VERSION 5.7 ;
BUSBITCHARS "[]" ;
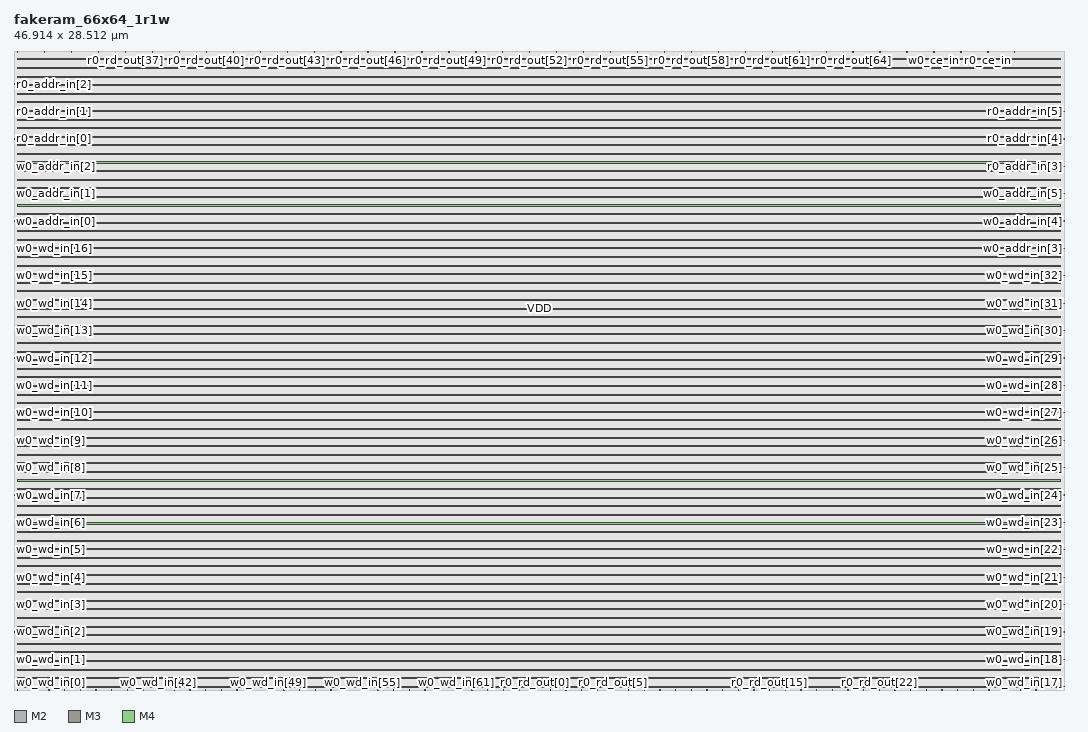
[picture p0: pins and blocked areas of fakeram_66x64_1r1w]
MACRO fakeram_66x64_1r1w
  FOREIGN fakeram_66x64_1r1w 0 0 ;
  SYMMETRY X Y R90 ;
  SIZE 46.914 BY 28.512 ;
  CLASS BLOCK ;
  PIN w0_wd_in[0]
    DIRECTION INPUT ;
    USE SIGNAL ;
    SHAPE ABUTMENT ;
    PORT
      LAYER M2 ;
      RECT 0.000 0.138 0.036 0.150 ;
    END
  END w0_wd_in[0]
  PIN w0_wd_in[1]
    DIRECTION INPUT ;
    USE SIGNAL ;
    SHAPE ABUTMENT ;
    PORT
      LAYER M2 ;
      RECT 0.000 1.362 0.036 1.374 ;
    END
  END w0_wd_in[1]
  PIN w0_wd_in[2]
    DIRECTION INPUT ;
    USE SIGNAL ;
    SHAPE ABUTMENT ;
    PORT
      LAYER M2 ;
      RECT 0.000 2.586 0.036 2.598 ;
    END
  END w0_wd_in[2]
  PIN w0_wd_in[3]
    DIRECTION INPUT ;
    USE SIGNAL ;
    SHAPE ABUTMENT ;
    PORT
      LAYER M2 ;
      RECT 0.000 3.810 0.036 3.822 ;
    END
  END w0_wd_in[3]
  PIN w0_wd_in[4]
    DIRECTION INPUT ;
    USE SIGNAL ;
    SHAPE ABUTMENT ;
    PORT
      LAYER M2 ;
      RECT 0.000 5.034 0.036 5.046 ;
    END
  END w0_wd_in[4]
  PIN w0_wd_in[5]
    DIRECTION INPUT ;
    USE SIGNAL ;
    SHAPE ABUTMENT ;
    PORT
      LAYER M2 ;
      RECT 0.000 6.258 0.036 6.270 ;
    END
  END w0_wd_in[5]
  PIN w0_wd_in[6]
    DIRECTION INPUT ;
    USE SIGNAL ;
    SHAPE ABUTMENT ;
    PORT
      LAYER M2 ;
      RECT 0.000 7.482 0.036 7.494 ;
    END
  END w0_wd_in[6]
  PIN w0_wd_in[7]
    DIRECTION INPUT ;
    USE SIGNAL ;
    SHAPE ABUTMENT ;
    PORT
      LAYER M2 ;
      RECT 0.000 8.706 0.036 8.718 ;
    END
  END w0_wd_in[7]
  PIN w0_wd_in[8]
    DIRECTION INPUT ;
    USE SIGNAL ;
    SHAPE ABUTMENT ;
    PORT
      LAYER M2 ;
      RECT 0.000 9.930 0.036 9.942 ;
    END
  END w0_wd_in[8]
  PIN w0_wd_in[9]
    DIRECTION INPUT ;
    USE SIGNAL ;
    SHAPE ABUTMENT ;
    PORT
      LAYER M2 ;
      RECT 0.000 11.154 0.036 11.166 ;
    END
  END w0_wd_in[9]
  PIN w0_wd_in[10]
    DIRECTION INPUT ;
    USE SIGNAL ;
    SHAPE ABUTMENT ;
    PORT
      LAYER M2 ;
      RECT 0.000 12.378 0.036 12.390 ;
    END
  END w0_wd_in[10]
  PIN w0_wd_in[11]
    DIRECTION INPUT ;
    USE SIGNAL ;
    SHAPE ABUTMENT ;
    PORT
      LAYER M2 ;
      RECT 0.000 13.602 0.036 13.614 ;
    END
  END w0_wd_in[11]
  PIN w0_wd_in[12]
    DIRECTION INPUT ;
    USE SIGNAL ;
    SHAPE ABUTMENT ;
    PORT
      LAYER M2 ;
      RECT 0.000 14.826 0.036 14.838 ;
    END
  END w0_wd_in[12]
  PIN w0_wd_in[13]
    DIRECTION INPUT ;
    USE SIGNAL ;
    SHAPE ABUTMENT ;
    PORT
      LAYER M2 ;
      RECT 0.000 16.050 0.036 16.062 ;
    END
  END w0_wd_in[13]
  PIN w0_wd_in[14]
    DIRECTION INPUT ;
    USE SIGNAL ;
    SHAPE ABUTMENT ;
    PORT
      LAYER M2 ;
      RECT 0.000 17.274 0.036 17.286 ;
    END
  END w0_wd_in[14]
  PIN w0_wd_in[15]
    DIRECTION INPUT ;
    USE SIGNAL ;
    SHAPE ABUTMENT ;
    PORT
      LAYER M2 ;
      RECT 0.000 18.498 0.036 18.510 ;
    END
  END w0_wd_in[15]
  PIN w0_wd_in[16]
    DIRECTION INPUT ;
    USE SIGNAL ;
    SHAPE ABUTMENT ;
    PORT
      LAYER M2 ;
      RECT 0.000 19.722 0.036 19.734 ;
    END
  END w0_wd_in[16]
  PIN w0_wd_in[17]
    DIRECTION INPUT ;
    USE SIGNAL ;
    SHAPE ABUTMENT ;
    PORT
      LAYER M2 ;
      RECT 46.878 0.138 46.914 0.150 ;
    END
  END w0_wd_in[17]
  PIN w0_wd_in[18]
    DIRECTION INPUT ;
    USE SIGNAL ;
    SHAPE ABUTMENT ;
    PORT
      LAYER M2 ;
      RECT 46.878 1.362 46.914 1.374 ;
    END
  END w0_wd_in[18]
  PIN w0_wd_in[19]
    DIRECTION INPUT ;
    USE SIGNAL ;
    SHAPE ABUTMENT ;
    PORT
      LAYER M2 ;
      RECT 46.878 2.586 46.914 2.598 ;
    END
  END w0_wd_in[19]
  PIN w0_wd_in[20]
    DIRECTION INPUT ;
    USE SIGNAL ;
    SHAPE ABUTMENT ;
    PORT
      LAYER M2 ;
      RECT 46.878 3.810 46.914 3.822 ;
    END
  END w0_wd_in[20]
  PIN w0_wd_in[21]
    DIRECTION INPUT ;
    USE SIGNAL ;
    SHAPE ABUTMENT ;
    PORT
      LAYER M2 ;
      RECT 46.878 5.034 46.914 5.046 ;
    END
  END w0_wd_in[21]
  PIN w0_wd_in[22]
    DIRECTION INPUT ;
    USE SIGNAL ;
    SHAPE ABUTMENT ;
    PORT
      LAYER M2 ;
      RECT 46.878 6.258 46.914 6.270 ;
    END
  END w0_wd_in[22]
  PIN w0_wd_in[23]
    DIRECTION INPUT ;
    USE SIGNAL ;
    SHAPE ABUTMENT ;
    PORT
      LAYER M2 ;
      RECT 46.878 7.482 46.914 7.494 ;
    END
  END w0_wd_in[23]
  PIN w0_wd_in[24]
    DIRECTION INPUT ;
    USE SIGNAL ;
    SHAPE ABUTMENT ;
    PORT
      LAYER M2 ;
      RECT 46.878 8.706 46.914 8.718 ;
    END
  END w0_wd_in[24]
  PIN w0_wd_in[25]
    DIRECTION INPUT ;
    USE SIGNAL ;
    SHAPE ABUTMENT ;
    PORT
      LAYER M2 ;
      RECT 46.878 9.930 46.914 9.942 ;
    END
  END w0_wd_in[25]
  PIN w0_wd_in[26]
    DIRECTION INPUT ;
    USE SIGNAL ;
    SHAPE ABUTMENT ;
    PORT
      LAYER M2 ;
      RECT 46.878 11.154 46.914 11.166 ;
    END
  END w0_wd_in[26]
  PIN w0_wd_in[27]
    DIRECTION INPUT ;
    USE SIGNAL ;
    SHAPE ABUTMENT ;
    PORT
      LAYER M2 ;
      RECT 46.878 12.378 46.914 12.390 ;
    END
  END w0_wd_in[27]
  PIN w0_wd_in[28]
    DIRECTION INPUT ;
    USE SIGNAL ;
    SHAPE ABUTMENT ;
    PORT
      LAYER M2 ;
      RECT 46.878 13.602 46.914 13.614 ;
    END
  END w0_wd_in[28]
  PIN w0_wd_in[29]
    DIRECTION INPUT ;
    USE SIGNAL ;
    SHAPE ABUTMENT ;
    PORT
      LAYER M2 ;
      RECT 46.878 14.826 46.914 14.838 ;
    END
  END w0_wd_in[29]
  PIN w0_wd_in[30]
    DIRECTION INPUT ;
    USE SIGNAL ;
    SHAPE ABUTMENT ;
    PORT
      LAYER M2 ;
      RECT 46.878 16.050 46.914 16.062 ;
    END
  END w0_wd_in[30]
  PIN w0_wd_in[31]
    DIRECTION INPUT ;
    USE SIGNAL ;
    SHAPE ABUTMENT ;
    PORT
      LAYER M2 ;
      RECT 46.878 17.274 46.914 17.286 ;
    END
  END w0_wd_in[31]
  PIN w0_wd_in[32]
    DIRECTION INPUT ;
    USE SIGNAL ;
    SHAPE ABUTMENT ;
    PORT
      LAYER M2 ;
      RECT 46.878 18.498 46.914 18.510 ;
    END
  END w0_wd_in[32]
  PIN w0_wd_in[33]
    DIRECTION INPUT ;
    USE SIGNAL ;
    SHAPE ABUTMENT ;
    PORT
      LAYER M3 ;
      RECT 0.161 0.000 0.175 0.042 ;
    END
  END w0_wd_in[33]
  PIN w0_wd_in[34]
    DIRECTION INPUT ;
    USE SIGNAL ;
    SHAPE ABUTMENT ;
    PORT
      LAYER M3 ;
      RECT 0.861 0.000 0.875 0.042 ;
    END
  END w0_wd_in[34]
  PIN w0_wd_in[35]
    DIRECTION INPUT ;
    USE SIGNAL ;
    SHAPE ABUTMENT ;
    PORT
      LAYER M3 ;
      RECT 1.561 0.000 1.575 0.042 ;
    END
  END w0_wd_in[35]
  PIN w0_wd_in[36]
    DIRECTION INPUT ;
    USE SIGNAL ;
    SHAPE ABUTMENT ;
    PORT
      LAYER M3 ;
      RECT 2.261 0.000 2.275 0.042 ;
    END
  END w0_wd_in[36]
  PIN w0_wd_in[37]
    DIRECTION INPUT ;
    USE SIGNAL ;
    SHAPE ABUTMENT ;
    PORT
      LAYER M3 ;
      RECT 2.961 0.000 2.975 0.042 ;
    END
  END w0_wd_in[37]
  PIN w0_wd_in[38]
    DIRECTION INPUT ;
    USE SIGNAL ;
    SHAPE ABUTMENT ;
    PORT
      LAYER M3 ;
      RECT 3.661 0.000 3.675 0.042 ;
    END
  END w0_wd_in[38]
  PIN w0_wd_in[39]
    DIRECTION INPUT ;
    USE SIGNAL ;
    SHAPE ABUTMENT ;
    PORT
      LAYER M3 ;
      RECT 4.361 0.000 4.375 0.042 ;
    END
  END w0_wd_in[39]
  PIN w0_wd_in[40]
    DIRECTION INPUT ;
    USE SIGNAL ;
    SHAPE ABUTMENT ;
    PORT
      LAYER M3 ;
      RECT 5.061 0.000 5.075 0.042 ;
    END
  END w0_wd_in[40]
  PIN w0_wd_in[41]
    DIRECTION INPUT ;
    USE SIGNAL ;
    SHAPE ABUTMENT ;
    PORT
      LAYER M3 ;
      RECT 5.761 0.000 5.775 0.042 ;
    END
  END w0_wd_in[41]
  PIN w0_wd_in[42]
    DIRECTION INPUT ;
    USE SIGNAL ;
    SHAPE ABUTMENT ;
    PORT
      LAYER M3 ;
      RECT 6.461 0.000 6.475 0.042 ;
    END
  END w0_wd_in[42]
  PIN w0_wd_in[43]
    DIRECTION INPUT ;
    USE SIGNAL ;
    SHAPE ABUTMENT ;
    PORT
      LAYER M3 ;
      RECT 7.161 0.000 7.175 0.042 ;
    END
  END w0_wd_in[43]
  PIN w0_wd_in[44]
    DIRECTION INPUT ;
    USE SIGNAL ;
    SHAPE ABUTMENT ;
    PORT
      LAYER M3 ;
      RECT 7.861 0.000 7.875 0.042 ;
    END
  END w0_wd_in[44]
  PIN w0_wd_in[45]
    DIRECTION INPUT ;
    USE SIGNAL ;
    SHAPE ABUTMENT ;
    PORT
      LAYER M3 ;
      RECT 8.561 0.000 8.575 0.042 ;
    END
  END w0_wd_in[45]
  PIN w0_wd_in[46]
    DIRECTION INPUT ;
    USE SIGNAL ;
    SHAPE ABUTMENT ;
    PORT
      LAYER M3 ;
      RECT 9.261 0.000 9.275 0.042 ;
    END
  END w0_wd_in[46]
  PIN w0_wd_in[47]
    DIRECTION INPUT ;
    USE SIGNAL ;
    SHAPE ABUTMENT ;
    PORT
      LAYER M3 ;
      RECT 9.961 0.000 9.975 0.042 ;
    END
  END w0_wd_in[47]
  PIN w0_wd_in[48]
    DIRECTION INPUT ;
    USE SIGNAL ;
    SHAPE ABUTMENT ;
    PORT
      LAYER M3 ;
      RECT 10.661 0.000 10.675 0.042 ;
    END
  END w0_wd_in[48]
  PIN w0_wd_in[49]
    DIRECTION INPUT ;
    USE SIGNAL ;
    SHAPE ABUTMENT ;
    PORT
      LAYER M3 ;
      RECT 11.361 0.000 11.375 0.042 ;
    END
  END w0_wd_in[49]
  PIN w0_wd_in[50]
    DIRECTION INPUT ;
    USE SIGNAL ;
    SHAPE ABUTMENT ;
    PORT
      LAYER M3 ;
      RECT 12.061 0.000 12.075 0.042 ;
    END
  END w0_wd_in[50]
  PIN w0_wd_in[51]
    DIRECTION INPUT ;
    USE SIGNAL ;
    SHAPE ABUTMENT ;
    PORT
      LAYER M3 ;
      RECT 12.761 0.000 12.775 0.042 ;
    END
  END w0_wd_in[51]
  PIN w0_wd_in[52]
    DIRECTION INPUT ;
    USE SIGNAL ;
    SHAPE ABUTMENT ;
    PORT
      LAYER M3 ;
      RECT 13.461 0.000 13.475 0.042 ;
    END
  END w0_wd_in[52]
  PIN w0_wd_in[53]
    DIRECTION INPUT ;
    USE SIGNAL ;
    SHAPE ABUTMENT ;
    PORT
      LAYER M3 ;
      RECT 14.161 0.000 14.175 0.042 ;
    END
  END w0_wd_in[53]
  PIN w0_wd_in[54]
    DIRECTION INPUT ;
    USE SIGNAL ;
    SHAPE ABUTMENT ;
    PORT
      LAYER M3 ;
      RECT 14.861 0.000 14.875 0.042 ;
    END
  END w0_wd_in[54]
  PIN w0_wd_in[55]
    DIRECTION INPUT ;
    USE SIGNAL ;
    SHAPE ABUTMENT ;
    PORT
      LAYER M3 ;
      RECT 15.561 0.000 15.575 0.042 ;
    END
  END w0_wd_in[55]
  PIN w0_wd_in[56]
    DIRECTION INPUT ;
    USE SIGNAL ;
    SHAPE ABUTMENT ;
    PORT
      LAYER M3 ;
      RECT 16.261 0.000 16.275 0.042 ;
    END
  END w0_wd_in[56]
  PIN w0_wd_in[57]
    DIRECTION INPUT ;
    USE SIGNAL ;
    SHAPE ABUTMENT ;
    PORT
      LAYER M3 ;
      RECT 16.961 0.000 16.975 0.042 ;
    END
  END w0_wd_in[57]
  PIN w0_wd_in[58]
    DIRECTION INPUT ;
    USE SIGNAL ;
    SHAPE ABUTMENT ;
    PORT
      LAYER M3 ;
      RECT 17.661 0.000 17.675 0.042 ;
    END
  END w0_wd_in[58]
  PIN w0_wd_in[59]
    DIRECTION INPUT ;
    USE SIGNAL ;
    SHAPE ABUTMENT ;
    PORT
      LAYER M3 ;
      RECT 18.361 0.000 18.375 0.042 ;
    END
  END w0_wd_in[59]
  PIN w0_wd_in[60]
    DIRECTION INPUT ;
    USE SIGNAL ;
    SHAPE ABUTMENT ;
    PORT
      LAYER M3 ;
      RECT 19.061 0.000 19.075 0.042 ;
    END
  END w0_wd_in[60]
  PIN w0_wd_in[61]
    DIRECTION INPUT ;
    USE SIGNAL ;
    SHAPE ABUTMENT ;
    PORT
      LAYER M3 ;
      RECT 19.761 0.000 19.775 0.042 ;
    END
  END w0_wd_in[61]
  PIN w0_wd_in[62]
    DIRECTION INPUT ;
    USE SIGNAL ;
    SHAPE ABUTMENT ;
    PORT
      LAYER M3 ;
      RECT 20.461 0.000 20.475 0.042 ;
    END
  END w0_wd_in[62]
  PIN w0_wd_in[63]
    DIRECTION INPUT ;
    USE SIGNAL ;
    SHAPE ABUTMENT ;
    PORT
      LAYER M3 ;
      RECT 21.161 0.000 21.175 0.042 ;
    END
  END w0_wd_in[63]
  PIN w0_wd_in[64]
    DIRECTION INPUT ;
    USE SIGNAL ;
    SHAPE ABUTMENT ;
    PORT
      LAYER M3 ;
      RECT 21.861 0.000 21.875 0.042 ;
    END
  END w0_wd_in[64]
  PIN w0_wd_in[65]
    DIRECTION INPUT ;
    USE SIGNAL ;
    SHAPE ABUTMENT ;
    PORT
      LAYER M3 ;
      RECT 22.561 0.000 22.575 0.042 ;
    END
  END w0_wd_in[65]
  PIN r0_rd_out[0]
    DIRECTION OUTPUT ;
    USE SIGNAL ;
    SHAPE ABUTMENT ;
    PORT
      LAYER M3 ;
      RECT 23.261 0.000 23.275 0.042 ;
    END
  END r0_rd_out[0]
  PIN r0_rd_out[1]
    DIRECTION OUTPUT ;
    USE SIGNAL ;
    SHAPE ABUTMENT ;
    PORT
      LAYER M3 ;
      RECT 23.961 0.000 23.975 0.042 ;
    END
  END r0_rd_out[1]
  PIN r0_rd_out[2]
    DIRECTION OUTPUT ;
    USE SIGNAL ;
    SHAPE ABUTMENT ;
    PORT
      LAYER M3 ;
      RECT 24.661 0.000 24.675 0.042 ;
    END
  END r0_rd_out[2]
  PIN r0_rd_out[3]
    DIRECTION OUTPUT ;
    USE SIGNAL ;
    SHAPE ABUTMENT ;
    PORT
      LAYER M3 ;
      RECT 25.361 0.000 25.375 0.042 ;
    END
  END r0_rd_out[3]
  PIN r0_rd_out[4]
    DIRECTION OUTPUT ;
    USE SIGNAL ;
    SHAPE ABUTMENT ;
    PORT
      LAYER M3 ;
      RECT 26.061 0.000 26.075 0.042 ;
    END
  END r0_rd_out[4]
  PIN r0_rd_out[5]
    DIRECTION OUTPUT ;
    USE SIGNAL ;
    SHAPE ABUTMENT ;
    PORT
      LAYER M3 ;
      RECT 26.761 0.000 26.775 0.042 ;
    END
  END r0_rd_out[5]
  PIN r0_rd_out[6]
    DIRECTION OUTPUT ;
    USE SIGNAL ;
    SHAPE ABUTMENT ;
    PORT
      LAYER M3 ;
      RECT 27.461 0.000 27.475 0.042 ;
    END
  END r0_rd_out[6]
  PIN r0_rd_out[7]
    DIRECTION OUTPUT ;
    USE SIGNAL ;
    SHAPE ABUTMENT ;
    PORT
      LAYER M3 ;
      RECT 28.161 0.000 28.175 0.042 ;
    END
  END r0_rd_out[7]
  PIN r0_rd_out[8]
    DIRECTION OUTPUT ;
    USE SIGNAL ;
    SHAPE ABUTMENT ;
    PORT
      LAYER M3 ;
      RECT 28.861 0.000 28.875 0.042 ;
    END
  END r0_rd_out[8]
  PIN r0_rd_out[9]
    DIRECTION OUTPUT ;
    USE SIGNAL ;
    SHAPE ABUTMENT ;
    PORT
      LAYER M3 ;
      RECT 29.561 0.000 29.575 0.042 ;
    END
  END r0_rd_out[9]
  PIN r0_rd_out[10]
    DIRECTION OUTPUT ;
    USE SIGNAL ;
    SHAPE ABUTMENT ;
    PORT
      LAYER M3 ;
      RECT 30.261 0.000 30.275 0.042 ;
    END
  END r0_rd_out[10]
  PIN r0_rd_out[11]
    DIRECTION OUTPUT ;
    USE SIGNAL ;
    SHAPE ABUTMENT ;
    PORT
      LAYER M3 ;
      RECT 30.961 0.000 30.975 0.042 ;
    END
  END r0_rd_out[11]
  PIN r0_rd_out[12]
    DIRECTION OUTPUT ;
    USE SIGNAL ;
    SHAPE ABUTMENT ;
    PORT
      LAYER M3 ;
      RECT 31.661 0.000 31.675 0.042 ;
    END
  END r0_rd_out[12]
  PIN r0_rd_out[13]
    DIRECTION OUTPUT ;
    USE SIGNAL ;
    SHAPE ABUTMENT ;
    PORT
      LAYER M3 ;
      RECT 32.361 0.000 32.375 0.042 ;
    END
  END r0_rd_out[13]
  PIN r0_rd_out[14]
    DIRECTION OUTPUT ;
    USE SIGNAL ;
    SHAPE ABUTMENT ;
    PORT
      LAYER M3 ;
      RECT 33.061 0.000 33.075 0.042 ;
    END
  END r0_rd_out[14]
  PIN r0_rd_out[15]
    DIRECTION OUTPUT ;
    USE SIGNAL ;
    SHAPE ABUTMENT ;
    PORT
      LAYER M3 ;
      RECT 33.761 0.000 33.775 0.042 ;
    END
  END r0_rd_out[15]
  PIN r0_rd_out[16]
    DIRECTION OUTPUT ;
    USE SIGNAL ;
    SHAPE ABUTMENT ;
    PORT
      LAYER M3 ;
      RECT 34.461 0.000 34.475 0.042 ;
    END
  END r0_rd_out[16]
  PIN r0_rd_out[17]
    DIRECTION OUTPUT ;
    USE SIGNAL ;
    SHAPE ABUTMENT ;
    PORT
      LAYER M3 ;
      RECT 35.161 0.000 35.175 0.042 ;
    END
  END r0_rd_out[17]
  PIN r0_rd_out[18]
    DIRECTION OUTPUT ;
    USE SIGNAL ;
    SHAPE ABUTMENT ;
    PORT
      LAYER M3 ;
      RECT 35.861 0.000 35.875 0.042 ;
    END
  END r0_rd_out[18]
  PIN r0_rd_out[19]
    DIRECTION OUTPUT ;
    USE SIGNAL ;
    SHAPE ABUTMENT ;
    PORT
      LAYER M3 ;
      RECT 36.561 0.000 36.575 0.042 ;
    END
  END r0_rd_out[19]
  PIN r0_rd_out[20]
    DIRECTION OUTPUT ;
    USE SIGNAL ;
    SHAPE ABUTMENT ;
    PORT
      LAYER M3 ;
      RECT 37.261 0.000 37.275 0.042 ;
    END
  END r0_rd_out[20]
  PIN r0_rd_out[21]
    DIRECTION OUTPUT ;
    USE SIGNAL ;
    SHAPE ABUTMENT ;
    PORT
      LAYER M3 ;
      RECT 37.961 0.000 37.975 0.042 ;
    END
  END r0_rd_out[21]
  PIN r0_rd_out[22]
    DIRECTION OUTPUT ;
    USE SIGNAL ;
    SHAPE ABUTMENT ;
    PORT
      LAYER M3 ;
      RECT 38.661 0.000 38.675 0.042 ;
    END
  END r0_rd_out[22]
  PIN r0_rd_out[23]
    DIRECTION OUTPUT ;
    USE SIGNAL ;
    SHAPE ABUTMENT ;
    PORT
      LAYER M3 ;
      RECT 39.361 0.000 39.375 0.042 ;
    END
  END r0_rd_out[23]
  PIN r0_rd_out[24]
    DIRECTION OUTPUT ;
    USE SIGNAL ;
    SHAPE ABUTMENT ;
    PORT
      LAYER M3 ;
      RECT 40.061 0.000 40.075 0.042 ;
    END
  END r0_rd_out[24]
  PIN r0_rd_out[25]
    DIRECTION OUTPUT ;
    USE SIGNAL ;
    SHAPE ABUTMENT ;
    PORT
      LAYER M3 ;
      RECT 40.761 0.000 40.775 0.042 ;
    END
  END r0_rd_out[25]
  PIN r0_rd_out[26]
    DIRECTION OUTPUT ;
    USE SIGNAL ;
    SHAPE ABUTMENT ;
    PORT
      LAYER M3 ;
      RECT 41.461 0.000 41.475 0.042 ;
    END
  END r0_rd_out[26]
  PIN r0_rd_out[27]
    DIRECTION OUTPUT ;
    USE SIGNAL ;
    SHAPE ABUTMENT ;
    PORT
      LAYER M3 ;
      RECT 42.161 0.000 42.175 0.042 ;
    END
  END r0_rd_out[27]
  PIN r0_rd_out[28]
    DIRECTION OUTPUT ;
    USE SIGNAL ;
    SHAPE ABUTMENT ;
    PORT
      LAYER M3 ;
      RECT 42.861 0.000 42.875 0.042 ;
    END
  END r0_rd_out[28]
  PIN r0_rd_out[29]
    DIRECTION OUTPUT ;
    USE SIGNAL ;
    SHAPE ABUTMENT ;
    PORT
      LAYER M3 ;
      RECT 43.561 0.000 43.575 0.042 ;
    END
  END r0_rd_out[29]
  PIN r0_rd_out[30]
    DIRECTION OUTPUT ;
    USE SIGNAL ;
    SHAPE ABUTMENT ;
    PORT
      LAYER M3 ;
      RECT 44.261 0.000 44.275 0.042 ;
    END
  END r0_rd_out[30]
  PIN r0_rd_out[31]
    DIRECTION OUTPUT ;
    USE SIGNAL ;
    SHAPE ABUTMENT ;
    PORT
      LAYER M3 ;
      RECT 44.961 0.000 44.975 0.042 ;
    END
  END r0_rd_out[31]
  PIN r0_rd_out[32]
    DIRECTION OUTPUT ;
    USE SIGNAL ;
    SHAPE ABUTMENT ;
    PORT
      LAYER M3 ;
      RECT 45.661 0.000 45.675 0.042 ;
    END
  END r0_rd_out[32]
  PIN r0_rd_out[33]
    DIRECTION OUTPUT ;
    USE SIGNAL ;
    SHAPE ABUTMENT ;
    PORT
      LAYER M3 ;
      RECT 0.161 28.470 0.175 28.512 ;
    END
  END r0_rd_out[33]
  PIN r0_rd_out[34]
    DIRECTION OUTPUT ;
    USE SIGNAL ;
    SHAPE ABUTMENT ;
    PORT
      LAYER M3 ;
      RECT 1.365 28.470 1.379 28.512 ;
    END
  END r0_rd_out[34]
  PIN r0_rd_out[35]
    DIRECTION OUTPUT ;
    USE SIGNAL ;
    SHAPE ABUTMENT ;
    PORT
      LAYER M3 ;
      RECT 2.569 28.470 2.583 28.512 ;
    END
  END r0_rd_out[35]
  PIN r0_rd_out[36]
    DIRECTION OUTPUT ;
    USE SIGNAL ;
    SHAPE ABUTMENT ;
    PORT
      LAYER M3 ;
      RECT 3.773 28.470 3.787 28.512 ;
    END
  END r0_rd_out[36]
  PIN r0_rd_out[37]
    DIRECTION OUTPUT ;
    USE SIGNAL ;
    SHAPE ABUTMENT ;
    PORT
      LAYER M3 ;
      RECT 4.977 28.470 4.991 28.512 ;
    END
  END r0_rd_out[37]
  PIN r0_rd_out[38]
    DIRECTION OUTPUT ;
    USE SIGNAL ;
    SHAPE ABUTMENT ;
    PORT
      LAYER M3 ;
      RECT 6.181 28.470 6.195 28.512 ;
    END
  END r0_rd_out[38]
  PIN r0_rd_out[39]
    DIRECTION OUTPUT ;
    USE SIGNAL ;
    SHAPE ABUTMENT ;
    PORT
      LAYER M3 ;
      RECT 7.385 28.470 7.399 28.512 ;
    END
  END r0_rd_out[39]
  PIN r0_rd_out[40]
    DIRECTION OUTPUT ;
    USE SIGNAL ;
    SHAPE ABUTMENT ;
    PORT
      LAYER M3 ;
      RECT 8.589 28.470 8.603 28.512 ;
    END
  END r0_rd_out[40]
  PIN r0_rd_out[41]
    DIRECTION OUTPUT ;
    USE SIGNAL ;
    SHAPE ABUTMENT ;
    PORT
      LAYER M3 ;
      RECT 9.793 28.470 9.807 28.512 ;
    END
  END r0_rd_out[41]
  PIN r0_rd_out[42]
    DIRECTION OUTPUT ;
    USE SIGNAL ;
    SHAPE ABUTMENT ;
    PORT
      LAYER M3 ;
      RECT 10.997 28.470 11.011 28.512 ;
    END
  END r0_rd_out[42]
  PIN r0_rd_out[43]
    DIRECTION OUTPUT ;
    USE SIGNAL ;
    SHAPE ABUTMENT ;
    PORT
      LAYER M3 ;
      RECT 12.201 28.470 12.215 28.512 ;
    END
  END r0_rd_out[43]
  PIN r0_rd_out[44]
    DIRECTION OUTPUT ;
    USE SIGNAL ;
    SHAPE ABUTMENT ;
    PORT
      LAYER M3 ;
      RECT 13.405 28.470 13.419 28.512 ;
    END
  END r0_rd_out[44]
  PIN r0_rd_out[45]
    DIRECTION OUTPUT ;
    USE SIGNAL ;
    SHAPE ABUTMENT ;
    PORT
      LAYER M3 ;
      RECT 14.609 28.470 14.623 28.512 ;
    END
  END r0_rd_out[45]
  PIN r0_rd_out[46]
    DIRECTION OUTPUT ;
    USE SIGNAL ;
    SHAPE ABUTMENT ;
    PORT
      LAYER M3 ;
      RECT 15.813 28.470 15.827 28.512 ;
    END
  END r0_rd_out[46]
  PIN r0_rd_out[47]
    DIRECTION OUTPUT ;
    USE SIGNAL ;
    SHAPE ABUTMENT ;
    PORT
      LAYER M3 ;
      RECT 17.017 28.470 17.031 28.512 ;
    END
  END r0_rd_out[47]
  PIN r0_rd_out[48]
    DIRECTION OUTPUT ;
    USE SIGNAL ;
    SHAPE ABUTMENT ;
    PORT
      LAYER M3 ;
      RECT 18.221 28.470 18.235 28.512 ;
    END
  END r0_rd_out[48]
  PIN r0_rd_out[49]
    DIRECTION OUTPUT ;
    USE SIGNAL ;
    SHAPE ABUTMENT ;
    PORT
      LAYER M3 ;
      RECT 19.425 28.470 19.439 28.512 ;
    END
  END r0_rd_out[49]
  PIN r0_rd_out[50]
    DIRECTION OUTPUT ;
    USE SIGNAL ;
    SHAPE ABUTMENT ;
    PORT
      LAYER M3 ;
      RECT 20.629 28.470 20.643 28.512 ;
    END
  END r0_rd_out[50]
  PIN r0_rd_out[51]
    DIRECTION OUTPUT ;
    USE SIGNAL ;
    SHAPE ABUTMENT ;
    PORT
      LAYER M3 ;
      RECT 21.833 28.470 21.847 28.512 ;
    END
  END r0_rd_out[51]
  PIN r0_rd_out[52]
    DIRECTION OUTPUT ;
    USE SIGNAL ;
    SHAPE ABUTMENT ;
    PORT
      LAYER M3 ;
      RECT 23.037 28.470 23.051 28.512 ;
    END
  END r0_rd_out[52]
  PIN r0_rd_out[53]
    DIRECTION OUTPUT ;
    USE SIGNAL ;
    SHAPE ABUTMENT ;
    PORT
      LAYER M3 ;
      RECT 24.241 28.470 24.255 28.512 ;
    END
  END r0_rd_out[53]
  PIN r0_rd_out[54]
    DIRECTION OUTPUT ;
    USE SIGNAL ;
    SHAPE ABUTMENT ;
    PORT
      LAYER M3 ;
      RECT 25.445 28.470 25.459 28.512 ;
    END
  END r0_rd_out[54]
  PIN r0_rd_out[55]
    DIRECTION OUTPUT ;
    USE SIGNAL ;
    SHAPE ABUTMENT ;
    PORT
      LAYER M3 ;
      RECT 26.649 28.470 26.663 28.512 ;
    END
  END r0_rd_out[55]
  PIN r0_rd_out[56]
    DIRECTION OUTPUT ;
    USE SIGNAL ;
    SHAPE ABUTMENT ;
    PORT
      LAYER M3 ;
      RECT 27.853 28.470 27.867 28.512 ;
    END
  END r0_rd_out[56]
  PIN r0_rd_out[57]
    DIRECTION OUTPUT ;
    USE SIGNAL ;
    SHAPE ABUTMENT ;
    PORT
      LAYER M3 ;
      RECT 29.057 28.470 29.071 28.512 ;
    END
  END r0_rd_out[57]
  PIN r0_rd_out[58]
    DIRECTION OUTPUT ;
    USE SIGNAL ;
    SHAPE ABUTMENT ;
    PORT
      LAYER M3 ;
      RECT 30.261 28.470 30.275 28.512 ;
    END
  END r0_rd_out[58]
  PIN r0_rd_out[59]
    DIRECTION OUTPUT ;
    USE SIGNAL ;
    SHAPE ABUTMENT ;
    PORT
      LAYER M3 ;
      RECT 31.465 28.470 31.479 28.512 ;
    END
  END r0_rd_out[59]
  PIN r0_rd_out[60]
    DIRECTION OUTPUT ;
    USE SIGNAL ;
    SHAPE ABUTMENT ;
    PORT
      LAYER M3 ;
      RECT 32.669 28.470 32.683 28.512 ;
    END
  END r0_rd_out[60]
  PIN r0_rd_out[61]
    DIRECTION OUTPUT ;
    USE SIGNAL ;
    SHAPE ABUTMENT ;
    PORT
      LAYER M3 ;
      RECT 33.873 28.470 33.887 28.512 ;
    END
  END r0_rd_out[61]
  PIN r0_rd_out[62]
    DIRECTION OUTPUT ;
    USE SIGNAL ;
    SHAPE ABUTMENT ;
    PORT
      LAYER M3 ;
      RECT 35.077 28.470 35.091 28.512 ;
    END
  END r0_rd_out[62]
  PIN r0_rd_out[63]
    DIRECTION OUTPUT ;
    USE SIGNAL ;
    SHAPE ABUTMENT ;
    PORT
      LAYER M3 ;
      RECT 36.281 28.470 36.295 28.512 ;
    END
  END r0_rd_out[63]
  PIN r0_rd_out[64]
    DIRECTION OUTPUT ;
    USE SIGNAL ;
    SHAPE ABUTMENT ;
    PORT
      LAYER M3 ;
      RECT 37.485 28.470 37.499 28.512 ;
    END
  END r0_rd_out[64]
  PIN r0_rd_out[65]
    DIRECTION OUTPUT ;
    USE SIGNAL ;
    SHAPE ABUTMENT ;
    PORT
      LAYER M3 ;
      RECT 38.689 28.470 38.703 28.512 ;
    END
  END r0_rd_out[65]
  PIN w0_addr_in[0]
    DIRECTION INPUT ;
    USE SIGNAL ;
    SHAPE ABUTMENT ;
    PORT
      LAYER M2 ;
      RECT 0.000 20.946 0.036 20.958 ;
    END
  END w0_addr_in[0]
  PIN w0_addr_in[1]
    DIRECTION INPUT ;
    USE SIGNAL ;
    SHAPE ABUTMENT ;
    PORT
      LAYER M2 ;
      RECT 0.000 22.170 0.036 22.182 ;
    END
  END w0_addr_in[1]
  PIN w0_addr_in[2]
    DIRECTION INPUT ;
    USE SIGNAL ;
    SHAPE ABUTMENT ;
    PORT
      LAYER M2 ;
      RECT 0.000 23.394 0.036 23.406 ;
    END
  END w0_addr_in[2]
  PIN w0_addr_in[3]
    DIRECTION INPUT ;
    USE SIGNAL ;
    SHAPE ABUTMENT ;
    PORT
      LAYER M2 ;
      RECT 46.878 19.722 46.914 19.734 ;
    END
  END w0_addr_in[3]
  PIN w0_addr_in[4]
    DIRECTION INPUT ;
    USE SIGNAL ;
    SHAPE ABUTMENT ;
    PORT
      LAYER M2 ;
      RECT 46.878 20.946 46.914 20.958 ;
    END
  END w0_addr_in[4]
  PIN w0_addr_in[5]
    DIRECTION INPUT ;
    USE SIGNAL ;
    SHAPE ABUTMENT ;
    PORT
      LAYER M2 ;
      RECT 46.878 22.170 46.914 22.182 ;
    END
  END w0_addr_in[5]
  PIN r0_addr_in[0]
    DIRECTION INPUT ;
    USE SIGNAL ;
    SHAPE ABUTMENT ;
    PORT
      LAYER M2 ;
      RECT 0.000 24.618 0.036 24.630 ;
    END
  END r0_addr_in[0]
  PIN r0_addr_in[1]
    DIRECTION INPUT ;
    USE SIGNAL ;
    SHAPE ABUTMENT ;
    PORT
      LAYER M2 ;
      RECT 0.000 25.842 0.036 25.854 ;
    END
  END r0_addr_in[1]
  PIN r0_addr_in[2]
    DIRECTION INPUT ;
    USE SIGNAL ;
    SHAPE ABUTMENT ;
    PORT
      LAYER M2 ;
      RECT 0.000 27.066 0.036 27.078 ;
    END
  END r0_addr_in[2]
  PIN r0_addr_in[3]
    DIRECTION INPUT ;
    USE SIGNAL ;
    SHAPE ABUTMENT ;
    PORT
      LAYER M2 ;
      RECT 46.878 23.394 46.914 23.406 ;
    END
  END r0_addr_in[3]
  PIN r0_addr_in[4]
    DIRECTION INPUT ;
    USE SIGNAL ;
    SHAPE ABUTMENT ;
    PORT
      LAYER M2 ;
      RECT 46.878 24.618 46.914 24.630 ;
    END
  END r0_addr_in[4]
  PIN r0_addr_in[5]
    DIRECTION INPUT ;
    USE SIGNAL ;
    SHAPE ABUTMENT ;
    PORT
      LAYER M2 ;
      RECT 46.878 25.842 46.914 25.854 ;
    END
  END r0_addr_in[5]
  PIN w0_we_in
    DIRECTION INPUT ;
    USE SIGNAL ;
    SHAPE ABUTMENT ;
    PORT
      LAYER M3 ;
      RECT 39.893 28.470 39.907 28.512 ;
    END
  END w0_we_in
  PIN w0_ce_in
    DIRECTION INPUT ;
    USE SIGNAL ;
    SHAPE ABUTMENT ;
    PORT
      LAYER M3 ;
      RECT 41.097 28.470 41.111 28.512 ;
    END
  END w0_ce_in
  PIN w0_clk
    DIRECTION INPUT ;
    USE SIGNAL ;
    SHAPE ABUTMENT ;
    PORT
      LAYER M3 ;
      RECT 42.301 28.470 42.315 28.512 ;
    END
  END w0_clk
  PIN r0_ce_in
    DIRECTION INPUT ;
    USE SIGNAL ;
    SHAPE ABUTMENT ;
    PORT
      LAYER M3 ;
      RECT 43.505 28.470 43.519 28.512 ;
    END
  END r0_ce_in
  PIN r0_clk
    DIRECTION INPUT ;
    USE SIGNAL ;
    SHAPE ABUTMENT ;
    PORT
      LAYER M3 ;
      RECT 44.709 28.470 44.723 28.512 ;
    END
  END r0_clk
  PIN VSS
    DIRECTION INOUT ;
    USE GROUND ;
    PORT
      LAYER M4 ;
      RECT 0.168 0.120 46.746 0.168 ;
      RECT 0.168 0.504 46.746 0.552 ;
      RECT 0.168 0.888 46.746 0.936 ;
      RECT 0.168 1.272 46.746 1.320 ;
      RECT 0.168 1.656 46.746 1.704 ;
      RECT 0.168 2.040 46.746 2.088 ;
      RECT 0.168 2.424 46.746 2.472 ;
      RECT 0.168 2.808 46.746 2.856 ;
      RECT 0.168 3.192 46.746 3.240 ;
      RECT 0.168 3.576 46.746 3.624 ;
      RECT 0.168 3.960 46.746 4.008 ;
      RECT 0.168 4.344 46.746 4.392 ;
      RECT 0.168 4.728 46.746 4.776 ;
      RECT 0.168 5.112 46.746 5.160 ;
      RECT 0.168 5.496 46.746 5.544 ;
      RECT 0.168 5.880 46.746 5.928 ;
      RECT 0.168 6.264 46.746 6.312 ;
      RECT 0.168 6.648 46.746 6.696 ;
      RECT 0.168 7.032 46.746 7.080 ;
      RECT 0.168 7.416 46.746 7.464 ;
      RECT 0.168 7.800 46.746 7.848 ;
      RECT 0.168 8.184 46.746 8.232 ;
      RECT 0.168 8.568 46.746 8.616 ;
      RECT 0.168 8.952 46.746 9.000 ;
      RECT 0.168 9.336 46.746 9.384 ;
      RECT 0.168 9.720 46.746 9.768 ;
      RECT 0.168 10.104 46.746 10.152 ;
      RECT 0.168 10.488 46.746 10.536 ;
      RECT 0.168 10.872 46.746 10.920 ;
      RECT 0.168 11.256 46.746 11.304 ;
      RECT 0.168 11.640 46.746 11.688 ;
      RECT 0.168 12.024 46.746 12.072 ;
      RECT 0.168 12.408 46.746 12.456 ;
      RECT 0.168 12.792 46.746 12.840 ;
      RECT 0.168 13.176 46.746 13.224 ;
      RECT 0.168 13.560 46.746 13.608 ;
      RECT 0.168 13.944 46.746 13.992 ;
      RECT 0.168 14.328 46.746 14.376 ;
      RECT 0.168 14.712 46.746 14.760 ;
      RECT 0.168 15.096 46.746 15.144 ;
      RECT 0.168 15.480 46.746 15.528 ;
      RECT 0.168 15.864 46.746 15.912 ;
      RECT 0.168 16.248 46.746 16.296 ;
      RECT 0.168 16.632 46.746 16.680 ;
      RECT 0.168 17.016 46.746 17.064 ;
      RECT 0.168 17.400 46.746 17.448 ;
      RECT 0.168 17.784 46.746 17.832 ;
      RECT 0.168 18.168 46.746 18.216 ;
      RECT 0.168 18.552 46.746 18.600 ;
      RECT 0.168 18.936 46.746 18.984 ;
      RECT 0.168 19.320 46.746 19.368 ;
      RECT 0.168 19.704 46.746 19.752 ;
      RECT 0.168 20.088 46.746 20.136 ;
      RECT 0.168 20.472 46.746 20.520 ;
      RECT 0.168 20.856 46.746 20.904 ;
      RECT 0.168 21.240 46.746 21.288 ;
      RECT 0.168 21.624 46.746 21.672 ;
      RECT 0.168 22.008 46.746 22.056 ;
      RECT 0.168 22.392 46.746 22.440 ;
      RECT 0.168 22.776 46.746 22.824 ;
      RECT 0.168 23.160 46.746 23.208 ;
      RECT 0.168 23.544 46.746 23.592 ;
      RECT 0.168 23.928 46.746 23.976 ;
      RECT 0.168 24.312 46.746 24.360 ;
      RECT 0.168 24.696 46.746 24.744 ;
      RECT 0.168 25.080 46.746 25.128 ;
      RECT 0.168 25.464 46.746 25.512 ;
      RECT 0.168 25.848 46.746 25.896 ;
      RECT 0.168 26.232 46.746 26.280 ;
      RECT 0.168 26.616 46.746 26.664 ;
      RECT 0.168 27.000 46.746 27.048 ;
      RECT 0.168 27.384 46.746 27.432 ;
      RECT 0.168 27.768 46.746 27.816 ;
      RECT 0.168 28.152 46.746 28.200 ;
    END
  END VSS
  PIN VDD
    DIRECTION INOUT ;
    USE POWER ;
    PORT
      LAYER M4 ;
      RECT 0.168 0.120 46.746 0.168 ;
      RECT 0.168 0.504 46.746 0.552 ;
      RECT 0.168 0.888 46.746 0.936 ;
      RECT 0.168 1.272 46.746 1.320 ;
      RECT 0.168 1.656 46.746 1.704 ;
      RECT 0.168 2.040 46.746 2.088 ;
      RECT 0.168 2.424 46.746 2.472 ;
      RECT 0.168 2.808 46.746 2.856 ;
      RECT 0.168 3.192 46.746 3.240 ;
      RECT 0.168 3.576 46.746 3.624 ;
      RECT 0.168 3.960 46.746 4.008 ;
      RECT 0.168 4.344 46.746 4.392 ;
      RECT 0.168 4.728 46.746 4.776 ;
      RECT 0.168 5.112 46.746 5.160 ;
      RECT 0.168 5.496 46.746 5.544 ;
      RECT 0.168 5.880 46.746 5.928 ;
      RECT 0.168 6.264 46.746 6.312 ;
      RECT 0.168 6.648 46.746 6.696 ;
      RECT 0.168 7.032 46.746 7.080 ;
      RECT 0.168 7.416 46.746 7.464 ;
      RECT 0.168 7.800 46.746 7.848 ;
      RECT 0.168 8.184 46.746 8.232 ;
      RECT 0.168 8.568 46.746 8.616 ;
      RECT 0.168 8.952 46.746 9.000 ;
      RECT 0.168 9.336 46.746 9.384 ;
      RECT 0.168 9.720 46.746 9.768 ;
      RECT 0.168 10.104 46.746 10.152 ;
      RECT 0.168 10.488 46.746 10.536 ;
      RECT 0.168 10.872 46.746 10.920 ;
      RECT 0.168 11.256 46.746 11.304 ;
      RECT 0.168 11.640 46.746 11.688 ;
      RECT 0.168 12.024 46.746 12.072 ;
      RECT 0.168 12.408 46.746 12.456 ;
      RECT 0.168 12.792 46.746 12.840 ;
      RECT 0.168 13.176 46.746 13.224 ;
      RECT 0.168 13.560 46.746 13.608 ;
      RECT 0.168 13.944 46.746 13.992 ;
      RECT 0.168 14.328 46.746 14.376 ;
      RECT 0.168 14.712 46.746 14.760 ;
      RECT 0.168 15.096 46.746 15.144 ;
      RECT 0.168 15.480 46.746 15.528 ;
      RECT 0.168 15.864 46.746 15.912 ;
      RECT 0.168 16.248 46.746 16.296 ;
      RECT 0.168 16.632 46.746 16.680 ;
      RECT 0.168 17.016 46.746 17.064 ;
      RECT 0.168 17.400 46.746 17.448 ;
      RECT 0.168 17.784 46.746 17.832 ;
      RECT 0.168 18.168 46.746 18.216 ;
      RECT 0.168 18.552 46.746 18.600 ;
      RECT 0.168 18.936 46.746 18.984 ;
      RECT 0.168 19.320 46.746 19.368 ;
      RECT 0.168 19.704 46.746 19.752 ;
      RECT 0.168 20.088 46.746 20.136 ;
      RECT 0.168 20.472 46.746 20.520 ;
      RECT 0.168 20.856 46.746 20.904 ;
      RECT 0.168 21.240 46.746 21.288 ;
      RECT 0.168 21.624 46.746 21.672 ;
      RECT 0.168 22.008 46.746 22.056 ;
      RECT 0.168 22.392 46.746 22.440 ;
      RECT 0.168 22.776 46.746 22.824 ;
      RECT 0.168 23.160 46.746 23.208 ;
      RECT 0.168 23.544 46.746 23.592 ;
      RECT 0.168 23.928 46.746 23.976 ;
      RECT 0.168 24.312 46.746 24.360 ;
      RECT 0.168 24.696 46.746 24.744 ;
      RECT 0.168 25.080 46.746 25.128 ;
      RECT 0.168 25.464 46.746 25.512 ;
      RECT 0.168 25.848 46.746 25.896 ;
      RECT 0.168 26.232 46.746 26.280 ;
      RECT 0.168 26.616 46.746 26.664 ;
      RECT 0.168 27.000 46.746 27.048 ;
      RECT 0.168 27.384 46.746 27.432 ;
      RECT 0.168 27.768 46.746 27.816 ;
      RECT 0.168 28.152 46.746 28.200 ;
    END
  END VDD
  OBS
    LAYER M1 ;
    RECT 0 0 46.914 28.512 ;
    LAYER M2 ;
    RECT 0 0 46.914 28.512 ;
    LAYER M3 ;
    RECT 0 0 46.914 28.512 ;
    LAYER M4 ;
    RECT 0 0 46.914 28.512 ;
  END
END fakeram_66x64_1r1w

END LIBRARY
